VERSION 5.7 ;
  NOWIREEXTENSIONATPIN ON ;
  DIVIDERCHAR "/" ;
  BUSBITCHARS "[]" ;
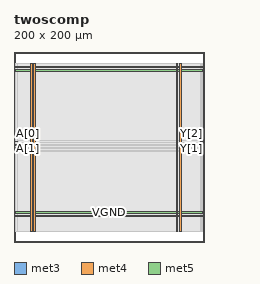
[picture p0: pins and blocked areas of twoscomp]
MACRO twoscomp
  CLASS BLOCK ;
  FOREIGN twoscomp ;
  ORIGIN 0.000 0.000 ;
  SIZE 200.000 BY 200.000 ;
  PIN A[0]
    DIRECTION INPUT ;
    USE SIGNAL ;
    ANTENNAGATEAREA 0.213000 ;
    PORT
      LAYER met3 ;
        RECT 0.000 105.440 4.000 106.040 ;
    END
  END A[0]
  PIN A[1]
    DIRECTION INPUT ;
    USE SIGNAL ;
    ANTENNAGATEAREA 0.126000 ;
    PORT
      LAYER met3 ;
        RECT 0.000 98.640 4.000 99.240 ;
    END
  END A[1]
  PIN A[2]
    DIRECTION INPUT ;
    USE SIGNAL ;
    ANTENNAGATEAREA 0.196500 ;
    PORT
      LAYER met3 ;
        RECT 0.000 95.240 4.000 95.840 ;
    END
  END A[2]
  PIN A[3]
    DIRECTION INPUT ;
    USE SIGNAL ;
    ANTENNAGATEAREA 0.196500 ;
    PORT
      LAYER met3 ;
        RECT 0.000 102.040 4.000 102.640 ;
    END
  END A[3]
  PIN VGND
    DIRECTION INOUT ;
    USE GROUND ;
    PORT
      LAYER met4 ;
        RECT 20.660 10.640 22.260 187.920 ;
    END
    PORT
      LAYER met4 ;
        RECT 174.260 10.640 175.860 187.920 ;
    END
    PORT
      LAYER met5 ;
        RECT 1.600 30.030 198.040 31.630 ;
    END
    PORT
      LAYER met5 ;
        RECT 1.600 183.210 198.040 184.810 ;
    END
  END VGND
  PIN VPWR
    DIRECTION INOUT ;
    USE POWER ;
    PORT
      LAYER met4 ;
        RECT 17.360 10.640 18.960 187.920 ;
    END
    PORT
      LAYER met4 ;
        RECT 170.960 10.640 172.560 187.920 ;
    END
    PORT
      LAYER met5 ;
        RECT 1.600 26.730 198.040 28.330 ;
    END
    PORT
      LAYER met5 ;
        RECT 1.600 179.910 198.040 181.510 ;
    END
  END VPWR
  PIN Y[0]
    DIRECTION OUTPUT ;
    USE SIGNAL ;
    ANTENNADIFFAREA 0.445500 ;
    PORT
      LAYER met3 ;
        RECT 196.000 95.240 200.000 95.840 ;
    END
  END Y[0]
  PIN Y[1]
    DIRECTION OUTPUT ;
    USE SIGNAL ;
    ANTENNADIFFAREA 0.445500 ;
    PORT
      LAYER met3 ;
        RECT 196.000 98.640 200.000 99.240 ;
    END
  END Y[1]
  PIN Y[2]
    DIRECTION OUTPUT ;
    USE SIGNAL ;
    ANTENNADIFFAREA 0.445500 ;
    PORT
      LAYER met3 ;
        RECT 196.000 105.440 200.000 106.040 ;
    END
  END Y[2]
  PIN Y[3]
    DIRECTION OUTPUT ;
    USE SIGNAL ;
    ANTENNADIFFAREA 0.445500 ;
    PORT
      LAYER met3 ;
        RECT 196.000 102.040 200.000 102.640 ;
    END
  END Y[3]
  OBS
      LAYER nwell ;
        RECT 1.650 10.795 197.990 187.870 ;
      LAYER li1 ;
        RECT 1.840 10.795 197.800 187.765 ;
      LAYER met1 ;
        RECT 1.840 10.640 197.800 187.920 ;
      LAYER met2 ;
        RECT 3.310 10.695 195.410 187.865 ;
      LAYER met3 ;
        RECT 3.285 106.440 196.000 187.845 ;
        RECT 4.400 105.040 195.600 106.440 ;
        RECT 3.285 103.040 196.000 105.040 ;
        RECT 4.400 101.640 195.600 103.040 ;
        RECT 3.285 99.640 196.000 101.640 ;
        RECT 4.400 98.240 195.600 99.640 ;
        RECT 3.285 96.240 196.000 98.240 ;
        RECT 4.400 94.840 195.600 96.240 ;
        RECT 3.285 10.715 196.000 94.840 ;
      LAYER met4 ;
        RECT 3.975 94.015 4.305 107.265 ;
  END
END twoscomp
END LIBRARY

